VERSION 5.7 ;
  NOWIREEXTENSIONATPIN ON ;
  DIVIDERCHAR "/" ;
  BUSBITCHARS "[]" ;
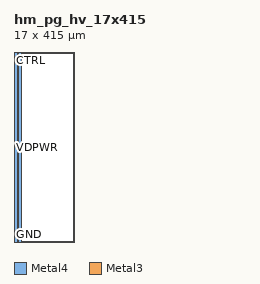
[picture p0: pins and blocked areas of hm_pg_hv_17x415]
MACRO hm_pg_hv_17x415
  CLASS BLOCK ;
  FOREIGN hm_pg_hv_17x415 ;
  ORIGIN 0.000 0.000 ;
  SIZE 17.000 BY 415.000 ;
  PIN GPWR
    ANTENNADIFFAREA 1281.275146 ;
    PORT
      LAYER Metal4 ;
        RECT 10.000 0.000 17.000 415.000 ;
    END
  END GPWR
  PIN VAPWR
    DIRECTION INOUT ;
    USE POWER ;
    PORT
      LAYER Metal4 ;
        RECT 0.000 0.000 7.000 415.000 ;
    END
  END VAPWR
  PIN VDPWR
    DIRECTION INOUT ;
    USE POWER ;
    PORT
      LAYER Metal4 ;
        RECT 8.650 0.000 9.700 415.000 ;
    END
  END VDPWR
  PIN GND
    DIRECTION INOUT ;
    USE GROUND ;
    PORT
      LAYER Metal4 ;
        RECT 7.300 0.000 8.350 415.000 ;
    END
  END GND
  PIN CTRL
    DIRECTION INPUT ;
    USE SIGNAL ;
    ANTENNAGATEAREA 0.390000 ;
    PORT
      LAYER Metal3 ;
        RECT 14.600 414.580 17.000 415.000 ;
    END
  END CTRL
  OBS
      LAYER GatPoly ;
        RECT 0.030 0.240 16.760 412.720 ;
      LAYER Metal1 ;
        RECT 0.000 0.240 17.000 413.230 ;
      LAYER Metal2 ;
        RECT 0.000 1.480 17.000 415.000 ;
      LAYER Metal3 ;
        RECT 0.000 0.000 17.000 413.020 ;
  END
END hm_pg_hv_17x415
END LIBRARY

